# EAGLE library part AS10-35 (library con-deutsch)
DEUTSCH Connector

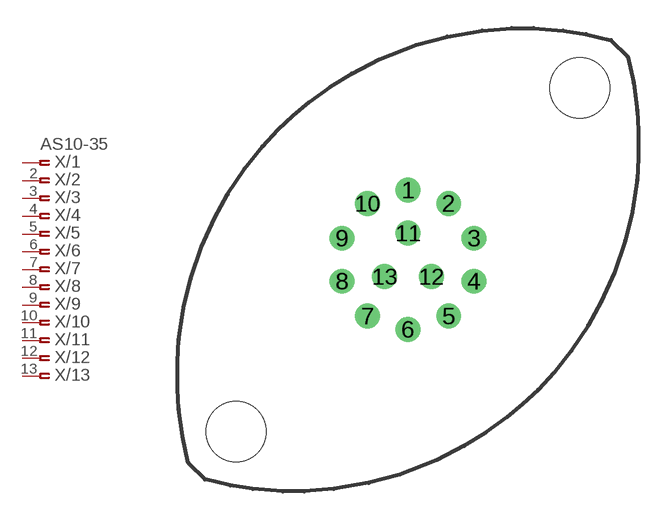
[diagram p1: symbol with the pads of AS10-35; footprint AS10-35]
Designator prefix X; gates /1=PINF_VAL /2=ASPINF /3=ASPINF /4=ASPINF /5=ASPINF /6=ASPINF /7=ASPINF /8=ASPINF /9=ASPINF /10=ASPINF /11=ASPINF /12=ASPINF /13=ASPINF

## AS10-35  [AS10-35]
1  /1:P$1  pas
2  /2:P$1  pas
3  /3:P$1  pas
4  /4:P$1  pas
5  /5:P$1  pas
6  /6:P$1  pas
7  /7:P$1  pas
8  /8:P$1  pas
9  /9:P$1  pas
10  /10:P$1  pas
11  /11:P$1  pas
12  /12:P$1  pas
13  /13:P$1  pas

## Footprint AS10-35 (pad centres in mm)
DEUTSCH Connector
drill 0.813 round: 1 0,3.708; 2 2.159,2.997; 3 3.505,1.143; 4 3.505,-1.143; 5 2.159,-2.997; 6 0,-3.708; 7 -2.159,-2.997; 8 -3.505,-1.143; 9 -3.505,1.143; 10 -2.159,2.997; 11 0,1.422; 12 1.245,-0.889; 13 -1.245,-0.889
hole 3.2 at 9.144,9.144
hole 3.2 at -9.144,-9.144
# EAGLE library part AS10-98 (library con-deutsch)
DEUTSCH Connector

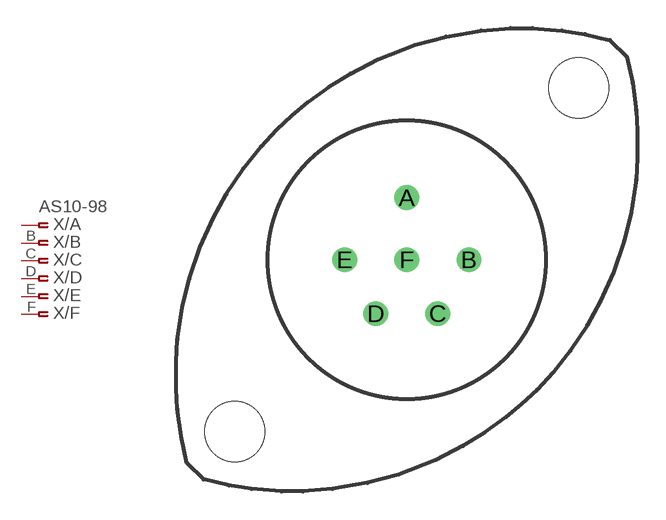
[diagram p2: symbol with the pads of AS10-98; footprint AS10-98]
Designator prefix X; gates /A=PINF_VAL /B=ASPINF /C=ASPINF /D=ASPINF /E=ASPINF /F=ASPINF

## AS10-98  [AS10-98]
A  /A:P$1  pas
B  /B:P$1  pas
C  /C:P$1  pas
D  /D:P$1  pas
E  /E:P$1  pas
F  /F:P$1  pas

## Footprint AS10-98 (pad centres in mm)
DEUTSCH Connector
drill 0.813 round: A 0,3.302; B 3.302,0; C 1.651,-2.87; D -1.651,-2.87; E -3.302,0; F 0,0
hole 3.2 at 9.144,9.144
hole 3.2 at -9.144,-9.144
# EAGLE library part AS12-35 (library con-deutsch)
DEUTSCH Connector

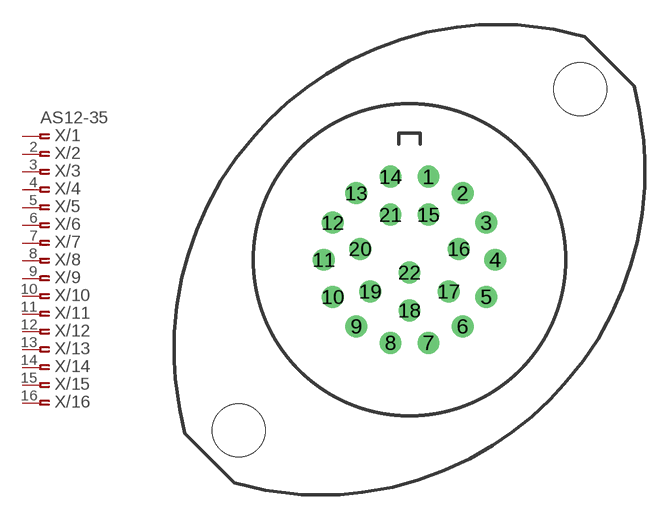
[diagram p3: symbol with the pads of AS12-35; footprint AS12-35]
Designator prefix X; gates /1=PINF_VAL /2=ASPINF /3=ASPINF /4=ASPINF /5=ASPINF /6=ASPINF /7=ASPINF /8=ASPINF /9=ASPINF /10=ASPINF /11=ASPINF /12=ASPINF /13=ASPINF /14=ASPINF /15=ASPINF /16=ASPINF /17=ASPINF /18=ASPINF /19=ASPINF /20=ASPINF /21=ASPINF /22=ASPINF

## AS12-35  [AS12-35]
1  /1:P$1  pas
2  /2:P$1  pas
3  /3:P$1  pas
4  /4:P$1  pas
5  /5:P$1  pas
6  /6:P$1  pas
7  /7:P$1  pas
8  /8:P$1  pas
9  /9:P$1  pas
10  /10:P$1  pas
11  /11:P$1  pas
12  /12:P$1  pas
13  /13:P$1  pas
14  /14:P$1  pas
15  /15:P$1  pas
16  /16:P$1  pas
17  /17:P$1  pas
18  /18:P$1  pas
19  /19:P$1  pas
20  /20:P$1  pas
21  /21:P$1  pas
22  /22:P$1  pas

## Footprint AS12-35 (pad centres in mm)
DEUTSCH Connector
drill 0.813 round: 1 1.143,5.004; 2 3.2,4.013; 3 4.623,2.235; 4 5.156,0; 5 4.623,-2.235; 6 3.2,-4.013; 7 1.143,-5.004; 8 -1.143,-5.004; 9 -3.2,-4.013; 10 -4.623,-2.235; 11 -5.156,0; 12 -4.623,2.235; 13 -3.2,4.013; 14 -1.143,5.004; 15 1.143,2.718; 16 2.972,0.66; 17 2.362,-1.905; 18 0,-3.048; 19 -2.362,-1.905; 20 -2.972,0.66; 21 -1.143,2.718; 22 0,-0.762
hole 3.2 at -10.287,-10.287
hole 3.2 at 10.287,10.287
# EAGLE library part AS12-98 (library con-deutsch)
DEUTSCH Connector

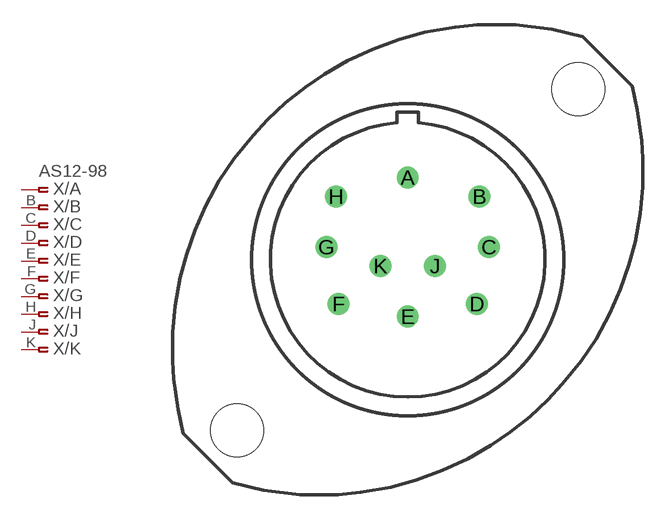
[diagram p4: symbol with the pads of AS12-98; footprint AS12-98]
Designator prefix X; gates /A=PINF_VAL /B=ASPINF /C=ASPINF /D=ASPINF /E=ASPINF /F=ASPINF /G=ASPINF /H=ASPINF /J=ASPINF /K=ASPINF

## AS12-98  [AS12-98]
A  /A:P$1  pas
B  /B:P$1  pas
C  /C:P$1  pas
D  /D:P$1  pas
E  /E:P$1  pas
F  /F:P$1  pas
G  /G:P$1  pas
H  /H:P$1  pas
J  /J:P$1  pas
K  /K:P$1  pas

## Footprint AS12-98 (pad centres in mm)
DEUTSCH Connector
drill 0.813 round: A 0,4.953; B 4.318,3.81; C 4.902,0.762; D 4.166,-2.667; E 0,-3.429; F -4.166,-2.667; G -4.902,0.762; H -4.318,3.81; J 1.651,-0.381; K -1.651,-0.381
hole 3.2 at -10.287,-10.287
hole 3.2 at 10.287,10.287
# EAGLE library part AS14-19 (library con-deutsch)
DEUTSCH Connector

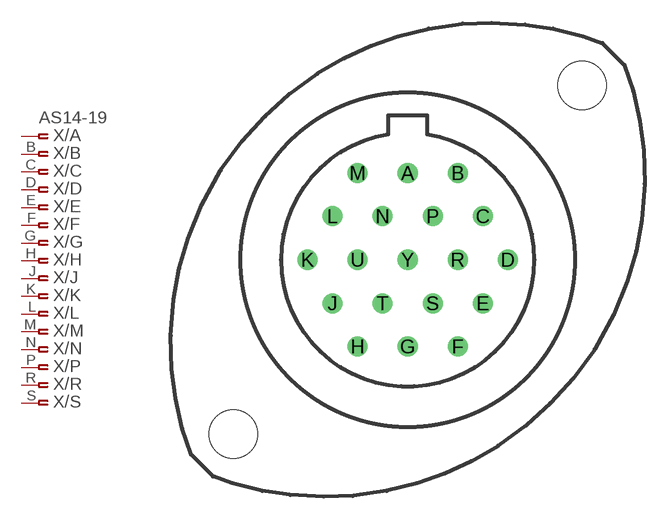
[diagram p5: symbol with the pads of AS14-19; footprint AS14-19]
Designator prefix X; gates /A=PINF_VAL /B=ASPINF /C=ASPINF /D=ASPINF /E=ASPINF /F=ASPINF /G=ASPINF /H=ASPINF /J=ASPINF /K=ASPINF /L=ASPINF /M=ASPINF /N=ASPINF /P=ASPINF /R=ASPINF /S=ASPINF /T=ASPINF /U=ASPINF /Y=ASPINF

## AS14-19  [AS14-19]
A  /A:P$1  pas
B  /B:P$1  pas
C  /C:P$1  pas
D  /D:P$1  pas
E  /E:P$1  pas
F  /F:P$1  pas
G  /G:P$1  pas
H  /H:P$1  pas
J  /J:P$1  pas
K  /K:P$1  pas
L  /L:P$1  pas
M  /M:P$1  pas
N  /N:P$1  pas
P  /P:P$1  pas
R  /R:P$1  pas
S  /S:P$1  pas
T  /T:P$1  pas
U  /U:P$1  pas
Y  /Y:P$1  pas

## Footprint AS14-19 (pad centres in mm)
DEUTSCH Connector
drill 0.813 round: A 0,5.715; B 3.302,5.715; C 4.953,2.87; D 6.604,0; E 4.953,-2.87; F 3.302,-5.715; G 0,-5.715; H -3.302,-5.715; J -4.953,-2.87; K -6.604,0; L -4.953,2.87; M -3.302,5.715; N -1.651,2.87; P 1.651,2.87; R 3.302,0; S 1.651,-2.87; T -1.651,-2.87; U -3.302,0; Y 0,0
hole 3.2 at 11.493,11.493
hole 3.2 at -11.493,-11.493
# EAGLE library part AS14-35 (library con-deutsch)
DEUTSCH Connector

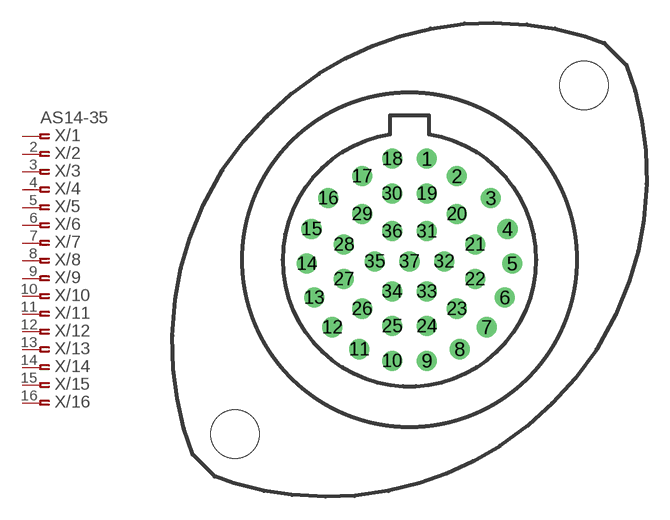
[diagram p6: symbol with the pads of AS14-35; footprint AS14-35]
Designator prefix X; gates /1=PINF_VAL /2=ASPINF /3=ASPINF /4=ASPINF /5=ASPINF /6=ASPINF /7=ASPINF /8=ASPINF /9=ASPINF /10=ASPINF /11=ASPINF /12=ASPINF /13=ASPINF /14=ASPINF /15=ASPINF /16=ASPINF /17=ASPINF /18=ASPINF /19=ASPINF /20=ASPINF /21=ASPINF /22=ASPINF /23=ASPINF /24=ASPINF /25=ASPINF /26=ASPINF /27=ASPINF /28=ASPINF /29=ASPINF /30=ASPINF /31=ASPINF /32=ASPINF /33=ASPINF /34=ASPINF /35=ASPINF /36=ASPINF /37=ASPINF

## AS14-35  [AS14-35]
1  /1:P$1  pas
2  /2:P$1  pas
3  /3:P$1  pas
4  /4:P$1  pas
5  /5:P$1  pas
6  /6:P$1  pas
7  /7:P$1  pas
8  /8:P$1  pas
9  /9:P$1  pas
10  /10:P$1  pas
11  /11:P$1  pas
12  /12:P$1  pas
13  /13:P$1  pas
14  /14:P$1  pas
15  /15:P$1  pas
16  /16:P$1  pas
17  /17:P$1  pas
18  /18:P$1  pas
19  /19:P$1  pas
20  /20:P$1  pas
21  /21:P$1  pas
22  /22:P$1  pas
23  /23:P$1  pas
24  /24:P$1  pas
25  /25:P$1  pas
26  /26:P$1  pas
27  /27:P$1  pas
28  /28:P$1  pas
29  /29:P$1  pas
30  /30:P$1  pas
31  /31:P$1  pas
32  /32:P$1  pas
33  /33:P$1  pas
34  /34:P$1  pas
35  /35:P$1  pas
36  /36:P$1  pas
37  /37:P$1  pas

## Footprint AS14-35 (pad centres in mm)
DEUTSCH Connector
drill 0.813 round: 1 1.143,6.655; 2 3.124,5.512; 3 5.359,4.064; 4 6.452,2.032; 5 6.756,-0.254; 6 6.274,-2.489; 7 5.08,-4.445; 8 3.302,-5.893; 9 1.143,-6.655; 10 -1.143,-6.655; 11 -3.302,-5.893; 12 -5.08,-4.445; 13 -6.274,-2.489; 14 -6.756,-0.254; 15 -6.452,2.032; 16 -5.359,4.064; 17 -3.124,5.512; 18 -1.143,6.655; 19 1.143,4.369; 20 3.124,3.023; 21 4.318,1.016; 22 4.318,-1.27; 23 3.124,-3.226; 24 1.143,-4.369; 25 -1.143,-4.369; 26 -3.124,-3.226; 27 -4.318,-1.27; 28 -4.318,1.016; 29 -3.124,3.023; 30 -1.143,4.369; 31 1.143,1.88; 32 2.286,-0.102; 33 1.143,-2.083; 34 -1.143,-2.083; 35 -2.286,-0.102; 36 -1.143,1.88; 37 0,-0.102
hole 3.2 at 11.493,11.493
hole 3.2 at -11.493,-11.493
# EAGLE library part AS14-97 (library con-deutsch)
DEUTSCH Connector

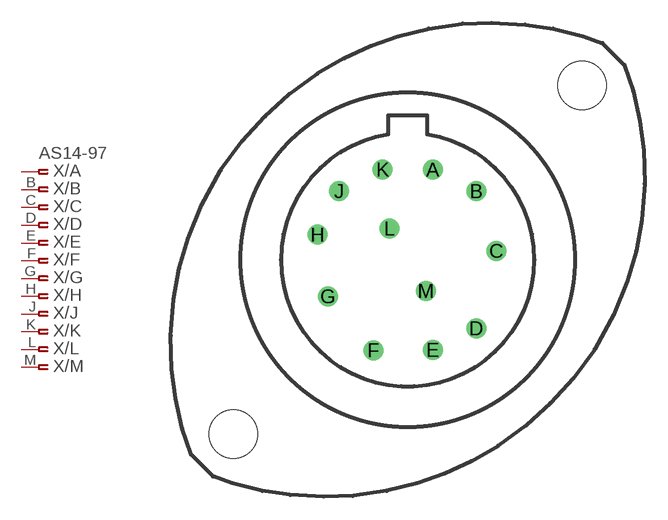
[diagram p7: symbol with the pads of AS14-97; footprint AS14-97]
Designator prefix X; gates /A=PINF_VAL /B=ASPINF /C=ASPINF /D=ASPINF /E=ASPINF /F=ASPINF /G=ASPINF /H=ASPINF /J=ASPINF /K=ASPINF /L=ASPINF /M=ASPINF

## AS14-97  [AS14-97]
A  /A:P$1  pas
B  /B:P$1  pas
C  /C:P$1  pas
D  /D:P$1  pas
E  /E:P$1  pas
F  /F:P$1  pas
G  /G:P$1  pas
H  /H:P$1  pas
J  /J:P$1  pas
K  /K:P$1  pas
L  /L:P$1  pas
M  /M:P$1  pas

## Footprint AS14-97 (pad centres in mm)
DEUTSCH Connector
drill 0.813 round: A 1.651,5.944; B 4.521,4.521; C 5.842,0.584; D 4.521,-4.521; E 1.651,-5.944; F -2.261,-5.969; G -5.258,-2.413; H -5.944,1.651; J -4.521,4.521; K -1.651,5.944; L -1.194,2.057; M 1.194,-2.057
hole 3.2 at 11.493,11.493
hole 3.2 at -11.493,-11.493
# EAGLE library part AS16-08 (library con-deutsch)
DEUTSCH Connector

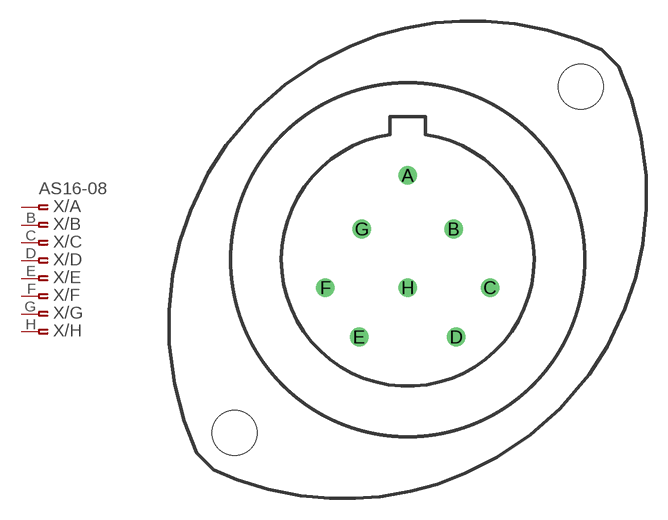
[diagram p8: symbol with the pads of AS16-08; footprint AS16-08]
Designator prefix X; gates /A=PINF_VAL /B=ASPINF /C=ASPINF /D=ASPINF /E=ASPINF /F=ASPINF /G=ASPINF /H=ASPINF

## AS16-08  [AS16-08]
A  /A:P$1  pas
B  /B:P$1  pas
C  /C:P$1  pas
D  /D:P$1  pas
E  /E:P$1  pas
F  /F:P$1  pas
G  /G:P$1  pas
H  /H:P$1  pas

## Footprint AS16-08 (pad centres in mm)
DEUTSCH Connector
drill 0.813 round: A 0,5.994; B 3.251,2.184; C 5.842,-1.981; D 3.454,-5.486; E -3.454,-5.486; F -5.842,-1.981; G -3.251,2.184; H 0,-1.981
hole 3.2 at 12.29,12.29
hole 3.2 at -12.29,-12.29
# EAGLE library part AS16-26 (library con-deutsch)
DEUTSCH Connector

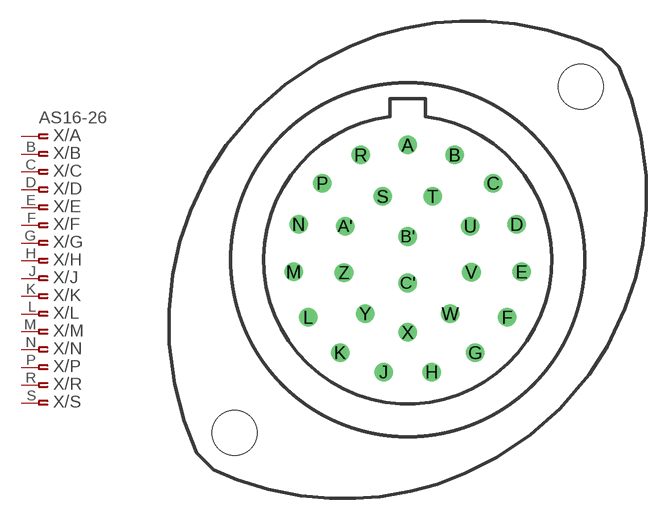
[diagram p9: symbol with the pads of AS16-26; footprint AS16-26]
Designator prefix X; gates /A=PINF_VAL /B=ASPINF /C=ASPINF /D=ASPINF /E=ASPINF /F=ASPINF /G=ASPINF /H=ASPINF /J=ASPINF /K=ASPINF /L=ASPINF /M=ASPINF /N=ASPINF /P=ASPINF /R=ASPINF /S=ASPINF /T=ASPINF /U=ASPINF /V=ASPINF /W=ASPINF /X=ASPINF /Y=ASPINF /Z=ASPINF /B'=ASPINF /C'=ASPINF /A'=ASPINF

## AS16-26  [AS16-26]
A  /A:P$1  pas
A'  /A':P$1  pas
B  /B:P$1  pas
B'  /B':P$1  pas
C  /C:P$1  pas
C'  /C':P$1  pas
D  /D:P$1  pas
E  /E:P$1  pas
F  /F:P$1  pas
G  /G:P$1  pas
H  /H:P$1  pas
J  /J:P$1  pas
K  /K:P$1  pas
L  /L:P$1  pas
M  /M:P$1  pas
N  /N:P$1  pas
P  /P:P$1  pas
R  /R:P$1  pas
S  /S:P$1  pas
T  /T:P$1  pas
U  /U:P$1  pas
V  /V:P$1  pas
W  /W:P$1  pas
X  /X:P$1  pas
Y  /Y:P$1  pas
Z  /Z:P$1  pas

## Footprint AS16-26 (pad centres in mm)
DEUTSCH Connector
drill 0.813 round: A 0,8.153; A' -4.445,2.388; B 3.327,7.442; B' 0,1.651; C 6.071,5.436; C' 0,-1.651; D 7.747,2.515; E 8.103,-0.864; F 7.061,-4.089; G 4.801,-6.604; H 1.702,-7.976; J -1.702,-7.976; K -4.801,-6.604; L -7.061,-4.089; M -8.103,-0.864; N -7.747,2.515; P -6.071,5.436; R -3.327,7.442; S -1.778,4.496; T 1.778,4.496; U 4.445,2.388; V 4.521,-0.889; W 3.023,-3.835; X 0,-5.156; Y -3.023,-3.835; Z -4.521,-0.914
hole 3.2 at 12.29,12.29
hole 3.2 at -12.29,-12.29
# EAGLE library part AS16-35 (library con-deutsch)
DEUTSCH Connector

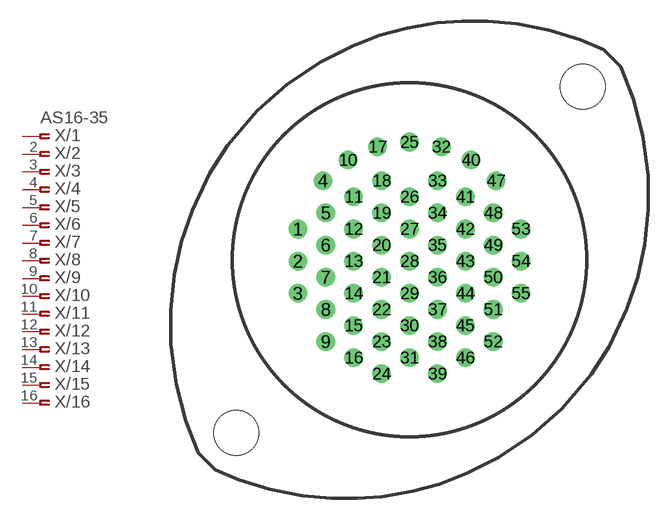
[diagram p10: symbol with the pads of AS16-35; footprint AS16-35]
Designator prefix X; gates /1=PINF_VAL /2=ASPINF /3=ASPINF /4=ASPINF /5=ASPINF /6=ASPINF /7=ASPINF /8=ASPINF /9=ASPINF /10=ASPINF /11=ASPINF /12=ASPINF /13=ASPINF /14=ASPINF /15=ASPINF /16=ASPINF /17=ASPINF /18=ASPINF /19=ASPINF /20=ASPINF /21=ASPINF /22=ASPINF /23=ASPINF /24=ASPINF /25=ASPINF /26=ASPINF /27=ASPINF /28=ASPINF /29=ASPINF /30=ASPINF /31=ASPINF /32=ASPINF /33=ASPINF /34=ASPINF /35=ASPINF /36=ASPINF /37=ASPINF /38=ASPINF /39=ASPINF /40=ASPINF /41=ASPINF /42=ASPINF /43=ASPINF /44=ASPINF /45=ASPINF /46=ASPINF /47=ASPINF /48=ASPINF /49=ASPINF /50=ASPINF /51=ASPINF /52=ASPINF /53=ASPINF /54=ASPINF /55=ASPINF

## AS16-35  [AS16-35]
1  /1:P$1  pas
2  /2:P$1  pas
3  /3:P$1  pas
4  /4:P$1  pas
5  /5:P$1  pas
6  /6:P$1  pas
7  /7:P$1  pas
8  /8:P$1  pas
9  /9:P$1  pas
10  /10:P$1  pas
11  /11:P$1  pas
12  /12:P$1  pas
13  /13:P$1  pas
14  /14:P$1  pas
15  /15:P$1  pas
16  /16:P$1  pas
17  /17:P$1  pas
18  /18:P$1  pas
19  /19:P$1  pas
20  /20:P$1  pas
21  /21:P$1  pas
22  /22:P$1  pas
23  /23:P$1  pas
24  /24:P$1  pas
25  /25:P$1  pas
26  /26:P$1  pas
27  /27:P$1  pas
28  /28:P$1  pas
29  /29:P$1  pas
30  /30:P$1  pas
31  /31:P$1  pas
32  /32:P$1  pas
33  /33:P$1  pas
34  /34:P$1  pas
35  /35:P$1  pas
36  /36:P$1  pas
37  /37:P$1  pas
38  /38:P$1  pas
39  /39:P$1  pas
40  /40:P$1  pas
41  /41:P$1  pas
42  /42:P$1  pas
43  /43:P$1  pas
44  /44:P$1  pas
45  /45:P$1  pas
46  /46:P$1  pas
47  /47:P$1  pas
48  /48:P$1  pas
49  /49:P$1  pas
50  /50:P$1  pas
51  /51:P$1  pas
52  /52:P$1  pas
53  /53:P$1  pas
54  /54:P$1  pas
55  /55:P$1  pas

## Footprint AS16-35 (pad centres in mm)
DEUTSCH Connector
drill 0.813 round: 1 -7.925,2.184; 2 -7.925,-0.102; 3 -7.925,-2.388; 4 -6.147,5.613; 5 -5.944,3.327; 6 -5.944,1.041; 7 -5.944,-1.245; 8 -5.944,-3.531; 9 -5.944,-5.817; 10 -4.369,7.087; 11 -3.962,4.47; 12 -3.962,2.184; 13 -3.962,-0.102; 14 -3.962,-2.388; 15 -3.962,-4.674; 16 -3.962,-6.96; 17 -2.261,8.026; 18 -1.981,5.613; 19 -1.981,3.327; 20 -1.981,1.041; 21 -1.981,-1.245; 22 -1.981,-3.531; 23 -1.981,-5.817; 24 -1.981,-8.103; 25 0,8.357; 26 0,4.47; 27 0,2.184; 28 0,-0.102; 29 0,-2.388; 30 0,-4.674; 31 0,-6.96; 32 2.261,8.026; 33 1.981,5.613; 34 1.981,3.327; 35 1.981,1.041; 36 1.981,-1.245; 37 1.981,-3.531; 38 1.981,-5.817; 39 1.981,-8.103; 40 4.369,7.087; 41 3.962,4.47; 42 3.962,2.184; 43 3.962,-0.102; 44 3.962,-2.388; 45 3.962,-4.674; 46 3.962,-6.96; 47 6.147,5.613; 48 5.944,3.327; 49 5.944,1.041; 50 5.944,-1.245; 51 5.944,-3.531; 52 5.944,-5.817; 53 7.925,2.184; 54 7.925,-0.102; 55 7.925,-2.388
hole 3.2 at 12.29,12.29
hole 3.2 at -12.29,-12.29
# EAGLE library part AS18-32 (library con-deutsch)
DEUTSCH Connector

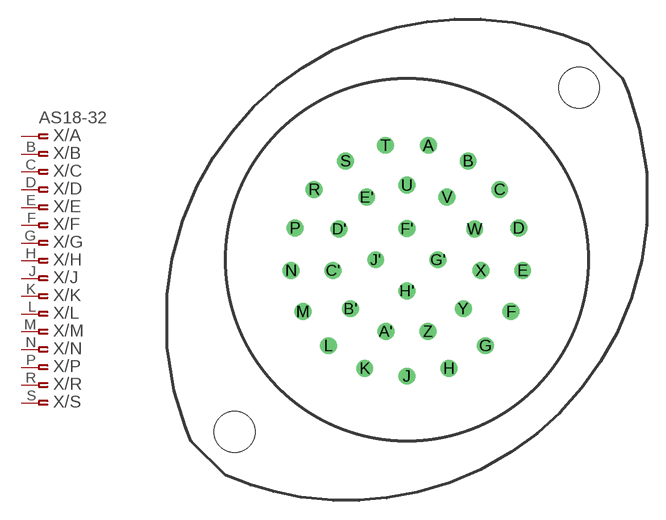
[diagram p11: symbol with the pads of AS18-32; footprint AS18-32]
Designator prefix X; gates /A=PINF_VAL /B=ASPINF /C=ASPINF /D=ASPINF /E=ASPINF /F=ASPINF /G=ASPINF /H=ASPINF /J=ASPINF /K=ASPINF /L=ASPINF /M=ASPINF /N=ASPINF /P=ASPINF /R=ASPINF /S=ASPINF /T=ASPINF /U=ASPINF /V=ASPINF /W=ASPINF /X=ASPINF /Y=ASPINF /Z=ASPINF /A'=PINF_VAL /B'=ASPINF /C'=ASPINF /D'=ASPINF /E'=ASPINF /F'=ASPINF /G'=ASPINF /H'=ASPINF /J'=ASPINF

## AS18-32  [AS18-32]
A  /A:P$1  pas
A'  /A':P$1  pas
B  /B:P$1  pas
B'  /B':P$1  pas
C  /C:P$1  pas
C'  /C':P$1  pas
D  /D:P$1  pas
D'  /D':P$1  pas
E  /E:P$1  pas
E'  /E':P$1  pas
F  /F:P$1  pas
F'  /F':P$1  pas
G  /G:P$1  pas
G'  /G':P$1  pas
H  /H:P$1  pas
H'  /H':P$1  pas
J  /J:P$1  pas
J'  /J':P$1  pas
K  /K:P$1  pas
L  /L:P$1  pas
M  /M:P$1  pas
N  /N:P$1  pas
P  /P:P$1  pas
R  /R:P$1  pas
S  /S:P$1  pas
T  /T:P$1  pas
U  /U:P$1  pas
V  /V:P$1  pas
W  /W:P$1  pas
X  /X:P$1  pas
Y  /Y:P$1  pas
Z  /Z:P$1  pas

## Footprint AS18-32 (pad centres in mm)
DEUTSCH Connector
drill 0.813 round: A 1.676,8.966; A' -1.651,-5.613; B 4.801,7.747; B' -4.42,-3.835; C 7.264,5.512; C' -5.791,-0.838; D 8.763,2.489; D' -5.309,2.413; E 9.068,-0.838; E' -3.15,4.902; F 8.153,-4.064; F' 0,2.438; G 6.147,-6.731; G' 2.438,0; H 3.302,-8.509; H' 0,-2.438; J 0,-9.119; J' -2.438,0; K -3.302,-8.509; L -6.147,-6.731; M -8.153,-4.064; N -9.068,-0.838; P -8.763,2.489; R -7.264,5.512; S -4.801,7.747; T -1.676,8.966; U 0,5.842; V 3.15,4.902; W 5.309,2.413; X 5.791,-0.838; Y 4.42,-3.835; Z 1.651,-5.613
hole 3.2 at -13.49,-13.49
hole 3.2 at 13.49,13.49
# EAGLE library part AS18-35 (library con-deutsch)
DEUTSCH Connector

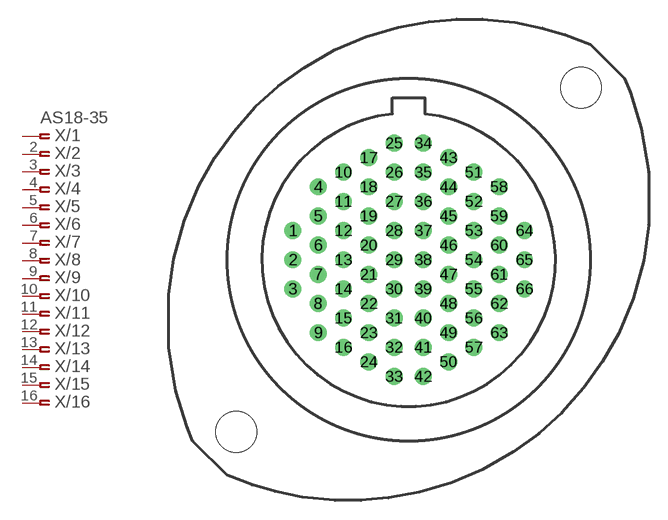
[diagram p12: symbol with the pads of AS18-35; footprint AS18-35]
Designator prefix X; gates /1=PINF_VAL /2=ASPINF /3=ASPINF /4=ASPINF /5=ASPINF /6=ASPINF /7=ASPINF /8=ASPINF /9=ASPINF /10=ASPINF /11=ASPINF /12=ASPINF /13=ASPINF /14=ASPINF /15=ASPINF /16=ASPINF /17=ASPINF /18=ASPINF /19=ASPINF /20=ASPINF /21=ASPINF /22=ASPINF /23=ASPINF /24=ASPINF /25=ASPINF /26=ASPINF /27=ASPINF /28=ASPINF /29=ASPINF /30=ASPINF /31=ASPINF /32=ASPINF /33=ASPINF /34=ASPINF /35=ASPINF /36=ASPINF /37=ASPINF /38=ASPINF /39=ASPINF /40=ASPINF /41=ASPINF /42=ASPINF /43=ASPINF /44=ASPINF /45=ASPINF /46=ASPINF /47=ASPINF /48=ASPINF /49=ASPINF /50=ASPINF /51=ASPINF /52=ASPINF /53=ASPINF /54=ASPINF /55=ASPINF /56=ASPINF /57=ASPINF /58=ASPINF /59=ASPINF /60=ASPINF /61=ASPINF /62=ASPINF /63=ASPINF /64=ASPINF /65=ASPINF /66=ASPINF

## AS18-35  [AS18-35]
1  /1:P$1  pas
2  /2:P$1  pas
3  /3:P$1  pas
4  /4:P$1  pas
5  /5:P$1  pas
6  /6:P$1  pas
7  /7:P$1  pas
8  /8:P$1  pas
9  /9:P$1  pas
10  /10:P$1  pas
11  /11:P$1  pas
12  /12:P$1  pas
13  /13:P$1  pas
14  /14:P$1  pas
15  /15:P$1  pas
16  /16:P$1  pas
17  /17:P$1  pas
18  /18:P$1  pas
19  /19:P$1  pas
20  /20:P$1  pas
21  /21:P$1  pas
22  /22:P$1  pas
23  /23:P$1  pas
24  /24:P$1  pas
25  /25:P$1  pas
26  /26:P$1  pas
27  /27:P$1  pas
28  /28:P$1  pas
29  /29:P$1  pas
30  /30:P$1  pas
31  /31:P$1  pas
32  /32:P$1  pas
33  /33:P$1  pas
34  /34:P$1  pas
35  /35:P$1  pas
36  /36:P$1  pas
37  /37:P$1  pas
38  /38:P$1  pas
39  /39:P$1  pas
40  /40:P$1  pas
41  /41:P$1  pas
42  /42:P$1  pas
43  /43:P$1  pas
44  /44:P$1  pas
45  /45:P$1  pas
46  /46:P$1  pas
47  /47:P$1  pas
48  /48:P$1  pas
49  /49:P$1  pas
50  /50:P$1  pas
51  /51:P$1  pas
52  /52:P$1  pas
53  /53:P$1  pas
54  /54:P$1  pas
55  /55:P$1  pas
56  /56:P$1  pas
57  /57:P$1  pas
58  /58:P$1  pas
59  /59:P$1  pas
60  /60:P$1  pas
61  /61:P$1  pas
62  /62:P$1  pas
63  /63:P$1  pas
64  /64:P$1  pas
65  /65:P$1  pas
66  /66:P$1  pas

## Footprint AS18-35 (pad centres in mm)
DEUTSCH Connector
drill 0.813 round: 1 -9.068,2.286; 2 -9.068,0; 3 -9.068,-2.286; 4 -7.087,5.715; 5 -7.087,3.429; 6 -7.087,1.143; 7 -7.087,-1.143; 8 -7.087,-3.429; 9 -7.087,-5.715; 10 -5.105,6.858; 11 -5.105,4.572; 12 -5.105,2.286; 13 -5.105,0; 14 -5.105,-2.286; 15 -5.105,-4.572; 16 -5.105,-6.858; 17 -3.124,8.001; 18 -3.124,5.715; 19 -3.124,3.429; 20 -3.124,1.143; 21 -3.124,-1.143; 22 -3.124,-3.429; 23 -3.124,-5.715; 24 -3.124,-8.001; 25 -1.143,9.144; 26 -1.143,6.858; 27 -1.143,4.572; 28 -1.143,2.286; 29 -1.143,0; 30 -1.143,-2.286; 31 -1.143,-4.572; 32 -1.143,-6.858; 33 -1.143,-9.144; 34 1.143,9.144; 35 1.143,6.858; 36 1.143,4.572; 37 1.143,2.286; 38 1.143,0; 39 1.143,-2.286; 40 1.143,-4.572; 41 1.143,-6.858; 42 1.143,-9.144; 43 3.124,8.001; 44 3.124,5.715; 45 3.124,3.429; 46 3.124,1.143; 47 3.124,-1.143; 48 3.124,-3.429; 49 3.124,-5.715; 50 3.124,-8.001; 51 5.105,6.858; 52 5.105,4.572; 53 5.105,2.286; 54 5.105,0; 55 5.105,-2.286; 56 5.105,-4.572; 57 5.105,-6.858; 58 7.087,5.715; 59 7.087,3.429; 60 7.087,1.143; 61 7.087,-1.143; 62 7.087,-3.429; 63 7.087,-5.715; 64 9.068,2.286; 65 9.068,0; 66 9.068,-2.286
hole 3.2 at -13.49,-13.49
hole 3.2 at 13.49,13.49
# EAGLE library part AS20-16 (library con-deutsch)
DEUTSCH Connector

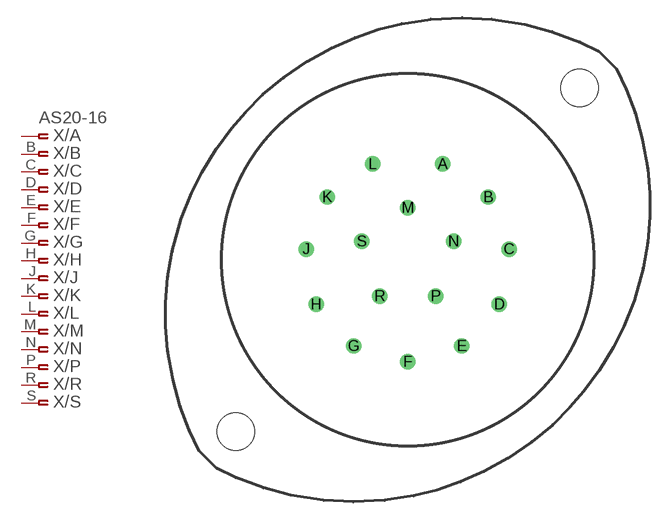
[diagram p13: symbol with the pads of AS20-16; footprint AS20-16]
Designator prefix X; gates /A=PINF_VAL /B=ASPINF /C=ASPINF /D=ASPINF /E=ASPINF /F=ASPINF /G=ASPINF /H=ASPINF /J=ASPINF /K=ASPINF /L=ASPINF /M=ASPINF /N=ASPINF /P=ASPINF /R=ASPINF /S=ASPINF

## AS20-16  [AS20-16]
A  /A:P$1  pas
B  /B:P$1  pas
C  /C:P$1  pas
D  /D:P$1  pas
E  /E:P$1  pas
F  /F:P$1  pas
G  /G:P$1  pas
H  /H:P$1  pas
J  /J:P$1  pas
K  /K:P$1  pas
L  /L:P$1  pas
M  /M:P$1  pas
N  /N:P$1  pas
P  /P:P$1  pas
R  /R:P$1  pas
S  /S:P$1  pas

## Footprint AS20-16 (pad centres in mm)
DEUTSCH Connector
drill 0.813 round: A 2.997,8.179; B 6.883,5.359; C 8.661,0.914; D 7.823,-3.81; E 4.623,-7.366; F 0,-8.712; G -4.623,-7.366; H -7.823,-3.81; J -8.661,0.914; K -6.883,5.359; L -2.997,8.179; M 0,4.445; N 3.912,1.575; P 2.388,-3.099; R -2.388,-3.099; S -3.912,1.575
hole 3.2 at -14.7,-14.7
hole 3.2 at 14.7,14.7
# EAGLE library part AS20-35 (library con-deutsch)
DEUTSCH Connector

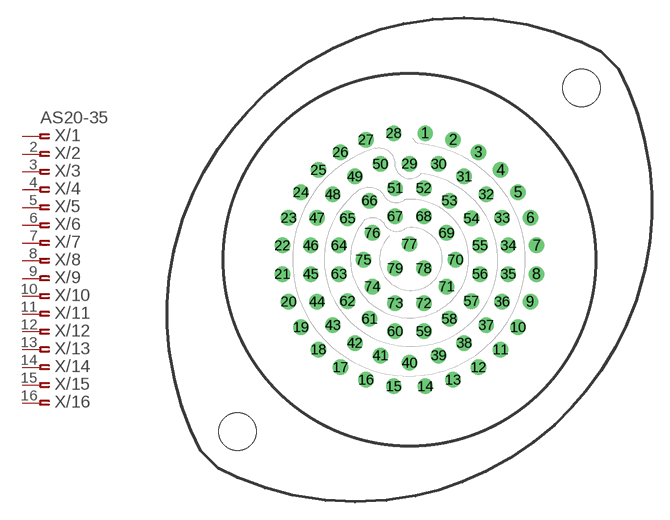
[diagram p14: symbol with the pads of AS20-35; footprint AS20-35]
Designator prefix X; gates /1=PINF_VAL /2=ASPINF /3=ASPINF /4=ASPINF /5=ASPINF /6=ASPINF /7=ASPINF /8=ASPINF /9=ASPINF /10=ASPINF /11=ASPINF /12=ASPINF /13=ASPINF /14=ASPINF /15=ASPINF /16=ASPINF /17=ASPINF /18=ASPINF /19=ASPINF /20=ASPINF /21=ASPINF /22=ASPINF /23=ASPINF /24=ASPINF /25=ASPINF /26=ASPINF /27=ASPINF /28=ASPINF /29=ASPINF /30=ASPINF /31=ASPINF /32=ASPINF /33=ASPINF /34=ASPINF /35=ASPINF /36=ASPINF /37=ASPINF /38=ASPINF /39=ASPINF /40=ASPINF /41=ASPINF /42=ASPINF /43=ASPINF /44=ASPINF /45=ASPINF /46=ASPINF /47=ASPINF /48=ASPINF /49=ASPINF /50=ASPINF /51=ASPINF /52=ASPINF /53=ASPINF /54=ASPINF /55=ASPINF /56=ASPINF /57=ASPINF /58=ASPINF /59=ASPINF /60=ASPINF /61=ASPINF /62=ASPINF /63=ASPINF /64=ASPINF /65=ASPINF /66=ASPINF /67=ASPINF /68=ASPINF /69=ASPINF /70=ASPINF /71=ASPINF /72=ASPINF /73=ASPINF /74=ASPINF /75=ASPINF /76=ASPINF /77=ASPINF /78=ASPINF /79=ASPINF

## AS20-35  [AS20-35]
1  /1:P$1  pas
2  /2:P$1  pas
3  /3:P$1  pas
4  /4:P$1  pas
5  /5:P$1  pas
6  /6:P$1  pas
7  /7:P$1  pas
8  /8:P$1  pas
9  /9:P$1  pas
10  /10:P$1  pas
11  /11:P$1  pas
12  /12:P$1  pas
13  /13:P$1  pas
14  /14:P$1  pas
15  /15:P$1  pas
16  /16:P$1  pas
17  /17:P$1  pas
18  /18:P$1  pas
19  /19:P$1  pas
20  /20:P$1  pas
21  /21:P$1  pas
22  /22:P$1  pas
23  /23:P$1  pas
24  /24:P$1  pas
25  /25:P$1  pas
26  /26:P$1  pas
27  /27:P$1  pas
28  /28:P$1  pas
29  /29:P$1  pas
30  /30:P$1  pas
31  /31:P$1  pas
32  /32:P$1  pas
33  /33:P$1  pas
34  /34:P$1  pas
35  /35:P$1  pas
36  /36:P$1  pas
37  /37:P$1  pas
38  /38:P$1  pas
39  /39:P$1  pas
40  /40:P$1  pas
41  /41:P$1  pas
42  /42:P$1  pas
43  /43:P$1  pas
44  /44:P$1  pas
45  /45:P$1  pas
46  /46:P$1  pas
47  /47:P$1  pas
48  /48:P$1  pas
49  /49:P$1  pas
50  /50:P$1  pas
51  /51:P$1  pas
52  /52:P$1  pas
53  /53:P$1  pas
54  /54:P$1  pas
55  /55:P$1  pas
56  /56:P$1  pas
57  /57:P$1  pas
58  /58:P$1  pas
59  /59:P$1  pas
60  /60:P$1  pas
61  /61:P$1  pas
62  /62:P$1  pas
63  /63:P$1  pas
64  /64:P$1  pas
65  /65:P$1  pas
66  /66:P$1  pas
67  /67:P$1  pas
68  /68:P$1  pas
69  /69:P$1  pas
70  /70:P$1  pas
71  /71:P$1  pas
72  /72:P$1  pas
73  /73:P$1  pas
74  /74:P$1  pas
75  /75:P$1  pas
76  /76:P$1  pas
77  /77:P$1  pas
78  /78:P$1  pas
79  /79:P$1  pas

## Footprint AS20-35 (pad centres in mm)
DEUTSCH Connector
drill 0.813 round: 1 1.346,10.82; 2 3.708,10.262; 3 5.893,9.195; 4 7.772,7.671; 5 9.271,5.766; 6 10.312,3.581; 7 10.846,1.219; 8 10.846,-1.219; 9 10.312,-3.581; 10 9.271,-5.766; 11 7.772,-7.671; 12 5.893,-9.195; 13 3.708,-10.262; 14 1.346,-10.82; 15 -1.346,-10.82; 16 -3.708,-10.262; 17 -5.893,-9.195; 18 -7.772,-7.671; 19 -9.271,-5.766; 20 -10.312,-3.581; 21 -10.846,-1.219; 22 -10.846,1.219; 23 -10.312,3.581; 24 -9.271,5.766; 25 -7.772,7.671; 26 -5.893,9.195; 27 -3.708,10.262; 28 -1.346,10.82; 29 0,8.204; 30 2.489,8.179; 31 4.674,7.112; 32 6.553,5.588; 33 7.899,3.581; 34 8.433,1.219; 35 8.433,-1.219; 36 7.899,-3.581; 37 6.553,-5.588; 38 4.674,-7.112; 39 2.489,-8.179; 40 0,-8.814; 41 -2.489,-8.179; 42 -4.674,-7.112; 43 -6.553,-5.588; 44 -7.899,-3.581; 45 -8.433,-1.219; 46 -8.433,1.219; 47 -7.899,3.581; 48 -6.553,5.588; 49 -4.674,7.112; 50 -2.489,8.179; 51 -1.219,6.121; 52 1.219,6.121; 53 3.404,5.055; 54 5.283,3.531; 55 6.02,1.219; 56 6.02,-1.219; 57 5.283,-3.531; 58 3.404,-5.055; 59 1.219,-6.121; 60 -1.219,-6.121; 61 -3.404,-5.055; 62 -5.283,-3.531; 63 -6.02,-1.219; 64 -6.02,1.219; 65 -5.283,3.531; 66 -3.404,5.055; 67 -1.219,3.708; 68 1.219,3.708; 69 3.175,2.286; 70 3.937,0; 71 3.175,-2.286; 72 1.219,-3.708; 73 -1.219,-3.708; 74 -3.175,-2.286; 75 -3.937,0; 76 -3.175,2.286; 77 0,1.346; 78 1.219,-0.737; 79 -1.219,-0.737
hole 3.2 at -14.7,-14.7
hole 3.2 at 14.7,14.7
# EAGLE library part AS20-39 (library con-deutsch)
DEUTSCH Connector

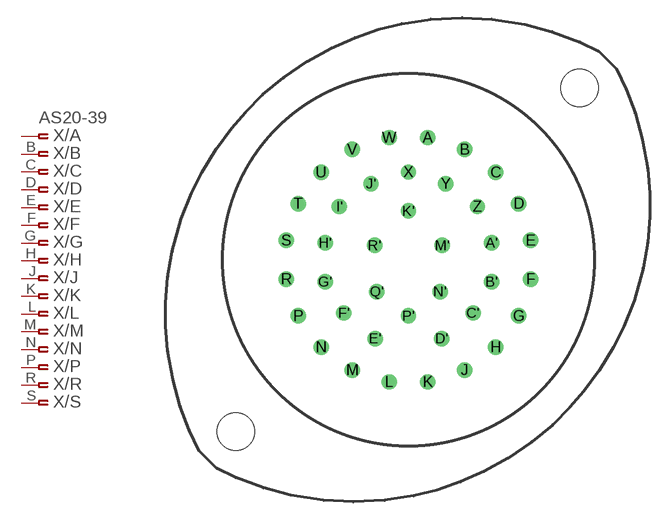
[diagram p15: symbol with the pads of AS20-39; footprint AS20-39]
Designator prefix X; gates /A=PINF_VAL /B=ASPINF /C=ASPINF /D=ASPINF /E=ASPINF /F=ASPINF /G=ASPINF /H=ASPINF /J=ASPINF /K=ASPINF /L=ASPINF /M=ASPINF /N=ASPINF /P=ASPINF /R=ASPINF /S=ASPINF /T=ASPINF /U=ASPINF /V=ASPINF /W=ASPINF /X=ASPINF /Y=ASPINF /Z=ASPINF /A'=PINF_VAL /B'=ASPINF /C'=ASPINF /D'=ASPINF /E'=ASPINF /F'=ASPINF /G'=ASPINF /H'=ASPINF /J'=ASPINF /K'=ASPINF /I'=ASPINF /M'=ASPINF /N'=ASPINF /P'=ASPINF /Q'=ASPINF /R'=ASPINF

## AS20-39  [AS20-39]
A  /A:P$1  pas
A'  /A':P$1  pas
B  /B:P$1  pas
B'  /B':P$1  pas
C  /C:P$1  pas
C'  /C':P$1  pas
D  /D:P$1  pas
D'  /D':P$1  pas
E  /E:P$1  pas
E'  /E':P$1  pas
F  /F:P$1  pas
F'  /F':P$1  pas
G  /G:P$1  pas
G'  /G':P$1  pas
H  /H:P$1  pas
H'  /H':P$1  pas
I'  /I':P$1  pas
J  /J:P$1  pas
J'  /J':P$1  pas
K  /K:P$1  pas
K'  /K':P$1  pas
L  /L:P$1  pas
M  /M:P$1  pas
M'  /M':P$1  pas
N  /N:P$1  pas
N'  /N':P$1  pas
P  /P:P$1  pas
P'  /P':P$1  pas
Q'  /Q':P$1  pas
R  /R:P$1  pas
R'  /R':P$1  pas
S  /S:P$1  pas
T  /T:P$1  pas
U  /U:P$1  pas
V  /V:P$1  pas
W  /W:P$1  pas
X  /X:P$1  pas
Y  /Y:P$1  pas
Z  /Z:P$1  pas

## Footprint AS20-39 (pad centres in mm)
DEUTSCH Connector
drill 0.813 round: A 1.651,10.439; A' 7.112,1.448; B 4.801,9.423; B' 7.112,-1.88; C 7.468,7.468; C' 5.512,-4.547; D 9.423,4.801; D' 2.845,-6.731; E 10.439,1.651; E' -2.845,-6.731; F 10.439,-1.651; F' -5.512,-4.547; G 9.423,-4.801; G' -7.112,-1.88; H 7.468,-7.468; H' -7.112,1.448; I' -5.893,4.547; J 4.801,-9.423; J' -3.2,6.502; K 1.651,-10.439; K' 0,4.166; L -1.651,-10.439; M -4.801,-9.423; M' 2.896,1.219; N -7.468,-7.468; N' 2.692,-2.718; P -9.423,-4.801; P' 0,-4.801; Q' -2.692,-2.718; R -10.439,-1.651; R' -2.896,1.219; S -10.439,1.651; T -9.423,4.801; U -7.468,7.468; V -4.801,9.423; W -1.651,10.439; X 0,7.493; Y 3.2,6.502; Z 5.893,4.547
hole 3.2 at -14.764,-14.7
hole 3.2 at 14.636,14.7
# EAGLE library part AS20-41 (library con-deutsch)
DEUTSCH Connector

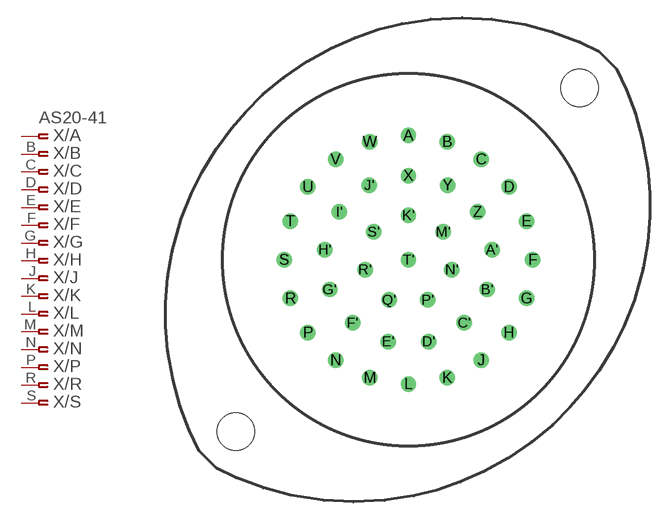
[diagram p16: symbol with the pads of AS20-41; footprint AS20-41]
Designator prefix X; gates /A=PINF_VAL /B=ASPINF /C=ASPINF /D=ASPINF /E=ASPINF /F=ASPINF /G=ASPINF /H=ASPINF /J=ASPINF /K=ASPINF /L=ASPINF /M=ASPINF /N=ASPINF /P=ASPINF /R=ASPINF /S=ASPINF /T=ASPINF /U=ASPINF /V=ASPINF /W=ASPINF /X=ASPINF /Y=ASPINF /Z=ASPINF /A'=PINF_VAL /B'=ASPINF /C'=ASPINF /D'=ASPINF /E'=ASPINF /F'=ASPINF /G'=ASPINF /H'=ASPINF /J'=ASPINF /K'=ASPINF /Q'=ASPINF /M'=ASPINF /N'=ASPINF /P'=ASPINF /R'=ASPINF /S'=ASPINF /T'=ASPINF /I'=ASPINF

## AS20-41  [AS20-41]
A  /A:P$1  pas
A'  /A':P$1  pas
B  /B:P$1  pas
B'  /B':P$1  pas
C  /C:P$1  pas
C'  /C':P$1  pas
D  /D:P$1  pas
D'  /D':P$1  pas
E  /E:P$1  pas
E'  /E':P$1  pas
F  /F:P$1  pas
F'  /F':P$1  pas
G  /G:P$1  pas
G'  /G':P$1  pas
H  /H:P$1  pas
H'  /H':P$1  pas
I'  /I':P$1  pas
J  /J:P$1  pas
J'  /J':P$1  pas
K  /K:P$1  pas
K'  /K':P$1  pas
L  /L:P$1  pas
M  /M:P$1  pas
M'  /M':P$1  pas
N  /N:P$1  pas
N'  /N':P$1  pas
P  /P:P$1  pas
P'  /P':P$1  pas
Q'  /Q':P$1  pas
R  /R:P$1  pas
R'  /R':P$1  pas
S  /S:P$1  pas
S'  /S':P$1  pas
T  /T:P$1  pas
T'  /T':P$1  pas
U  /U:P$1  pas
V  /V:P$1  pas
W  /W:P$1  pas
X  /X:P$1  pas
Y  /Y:P$1  pas
Z  /Z:P$1  pas

## Footprint AS20-41 (pad centres in mm)
DEUTSCH Connector
drill 0.813 round: A 0,10.617; A' 7.137,0.864; B 3.302,10.084; B' 6.731,-2.54; C 6.223,8.585; C' 4.775,-5.385; D 8.585,6.223; D' 1.727,-6.985; E 10.084,3.302; E' -1.727,-6.985; F 10.617,0; F' -4.775,-5.385; G 10.084,-3.302; G' -6.731,-2.54; H 8.585,-6.223; H' -7.137,0.864; I' -5.918,4.089; J 6.223,-8.585; J' -3.353,6.375; K 3.302,-10.084; K' 0,3.81; L 0,-10.617; M -3.302,-10.084; M' 2.972,2.388; N -6.223,-8.585; N' 3.708,-0.838; P -8.585,-6.223; P' 1.651,-3.429; Q' -1.651,-3.429; R -10.084,-3.302; R' -3.708,-0.838; S -10.617,0; S' -2.972,2.388; T -10.084,3.302; T' 0,0; U -8.585,6.223; V -6.223,8.585; W -3.302,10.084; X 0,7.188; Y 3.353,6.375; Z 5.918,4.089
hole 3.2 at -14.764,-14.7
hole 3.2 at 14.636,14.7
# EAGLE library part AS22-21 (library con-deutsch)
DEUTSCH Connector

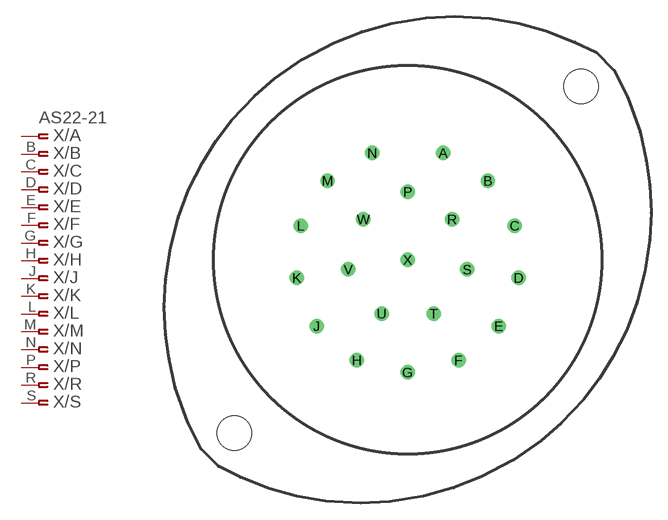
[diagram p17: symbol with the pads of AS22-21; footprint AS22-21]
Designator prefix X; gates /A=PINF_VAL /B=ASPINF /C=ASPINF /D=ASPINF /E=ASPINF /F=ASPINF /G=ASPINF /H=ASPINF /J=ASPINF /K=ASPINF /L=ASPINF /M=ASPINF /N=ASPINF /P=ASPINF /R=ASPINF /S=ASPINF /T=ASPINF /U=ASPINF /V=ASPINF /W=ASPINF /X=ASPINF

## AS22-21  [AS22-21]
A  /A:P$1  pas
B  /B:P$1  pas
C  /C:P$1  pas
D  /D:P$1  pas
E  /E:P$1  pas
F  /F:P$1  pas
G  /G:P$1  pas
H  /H:P$1  pas
J  /J:P$1  pas
K  /K:P$1  pas
L  /L:P$1  pas
M  /M:P$1  pas
N  /N:P$1  pas
P  /P:P$1  pas
R  /R:P$1  pas
S  /S:P$1  pas
T  /T:P$1  pas
U  /U:P$1  pas
V  /V:P$1  pas
W  /W:P$1  pas
X  /X:P$1  pas

## Footprint AS22-21 (pad centres in mm)
DEUTSCH Connector
drill 0.813 round: A 3.251,9.779; B 7.341,7.239; C 9.804,3.124; D 10.16,-1.651; E 8.331,-6.071; F 4.648,-9.195; G 0,-10.312; H -4.648,-9.195; J -8.331,-6.071; K -10.16,-1.651; L -9.804,3.124; M -7.341,7.239; N -3.251,9.779; P 0,6.223; R 4.064,3.708; S 5.436,-0.889; T 2.388,-4.928; U -2.388,-4.928; V -5.436,-0.889; W -4.064,3.708; X 0,0
hole 3.2 at -15.875,-15.875
hole 3.2 at 15.875,15.875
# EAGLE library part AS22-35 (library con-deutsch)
DEUTSCH Connector

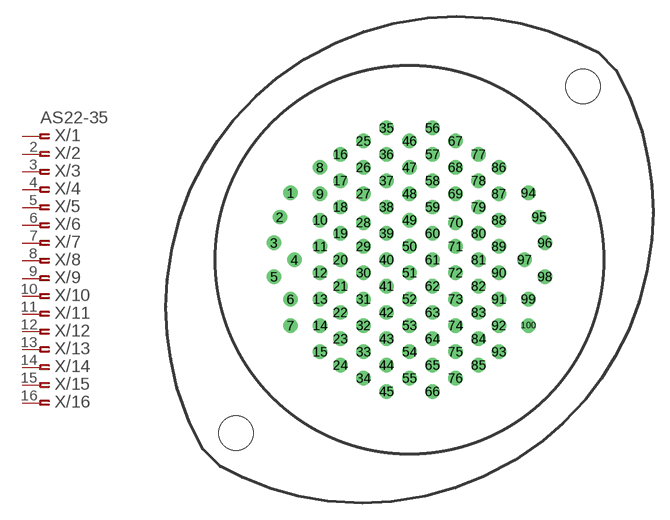
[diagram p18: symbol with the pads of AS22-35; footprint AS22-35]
Designator prefix X; gates /1=PINF_VAL /2=ASPINF /3=ASPINF /4=ASPINF /5=ASPINF /6=ASPINF /7=ASPINF /8=ASPINF /9=ASPINF /10=ASPINF /11=ASPINF /12=ASPINF /13=ASPINF /14=ASPINF /15=ASPINF /16=ASPINF /17=ASPINF /18=ASPINF /19=ASPINF /20=ASPINF /21=ASPINF /22=ASPINF /23=ASPINF /24=ASPINF /25=ASPINF /26=ASPINF /27=ASPINF /28=ASPINF /29=ASPINF /30=ASPINF /31=ASPINF /32=ASPINF /33=ASPINF /34=ASPINF /35=ASPINF /36=ASPINF /37=ASPINF /38=ASPINF /39=ASPINF /40=ASPINF /41=ASPINF /42=ASPINF /43=ASPINF /44=ASPINF /45=ASPINF /46=ASPINF /47=ASPINF /48=ASPINF /49=ASPINF /50=ASPINF /51=ASPINF /52=ASPINF /53=ASPINF /54=ASPINF /55=ASPINF /56=ASPINF /57=ASPINF /58=ASPINF /59=ASPINF /60=ASPINF /61=ASPINF /62=ASPINF /63=ASPINF /64=ASPINF /65=ASPINF /66=ASPINF /67=ASPINF /68=ASPINF /69=ASPINF /70=ASPINF /71=ASPINF /72=ASPINF /73=ASPINF /74=ASPINF /75=ASPINF /76=ASPINF /77=ASPINF /78=ASPINF /79=ASPINF /80=ASPINF /81=ASPINF /82=ASPINF /83=ASPINF /84=ASPINF /85=ASPINF /86=ASPINF /87=ASPINF /88=ASPINF /89=ASPINF /90=ASPINF /91=ASPINF /92=ASPINF /93=ASPINF /94=ASPINF /95=ASPINF /96=ASPINF /97=ASPINF /98=ASPINF /99=ASPINF /100=ASPINF

## AS22-35  [AS22-35]
1  /1:P$1  pas
2  /2:P$1  pas
3  /3:P$1  pas
4  /4:P$1  pas
5  /5:P$1  pas
6  /6:P$1  pas
7  /7:P$1  pas
8  /8:P$1  pas
9  /9:P$1  pas
10  /10:P$1  pas
11  /11:P$1  pas
12  /12:P$1  pas
13  /13:P$1  pas
14  /14:P$1  pas
15  /15:P$1  pas
16  /16:P$1  pas
17  /17:P$1  pas
18  /18:P$1  pas
19  /19:P$1  pas
20  /20:P$1  pas
21  /21:P$1  pas
22  /22:P$1  pas
23  /23:P$1  pas
24  /24:P$1  pas
25  /25:P$1  pas
26  /26:P$1  pas
27  /27:P$1  pas
28  /28:P$1  pas
29  /29:P$1  pas
30  /30:P$1  pas
31  /31:P$1  pas
32  /32:P$1  pas
33  /33:P$1  pas
34  /34:P$1  pas
35  /35:P$1  pas
36  /36:P$1  pas
37  /37:P$1  pas
38  /38:P$1  pas
39  /39:P$1  pas
40  /40:P$1  pas
41  /41:P$1  pas
42  /42:P$1  pas
43  /43:P$1  pas
44  /44:P$1  pas
45  /45:P$1  pas
46  /46:P$1  pas
47  /47:P$1  pas
48  /48:P$1  pas
49  /49:P$1  pas
50  /50:P$1  pas
51  /51:P$1  pas
52  /52:P$1  pas
53  /53:P$1  pas
54  /54:P$1  pas
55  /55:P$1  pas
56  /56:P$1  pas
57  /57:P$1  pas
58  /58:P$1  pas
59  /59:P$1  pas
60  /60:P$1  pas
61  /61:P$1  pas
62  /62:P$1  pas
63  /63:P$1  pas
64  /64:P$1  pas
65  /65:P$1  pas
66  /66:P$1  pas
67  /67:P$1  pas
68  /68:P$1  pas
69  /69:P$1  pas
70  /70:P$1  pas
71  /71:P$1  pas
72  /72:P$1  pas
73  /73:P$1  pas
74  /74:P$1  pas
75  /75:P$1  pas
76  /76:P$1  pas
77  /77:P$1  pas
78  /78:P$1  pas
79  /79:P$1  pas
80  /80:P$1  pas
81  /81:P$1  pas
82  /82:P$1  pas
83  /83:P$1  pas
84  /84:P$1  pas
85  /85:P$1  pas
86  /86:P$1  pas
87  /87:P$1  pas
88  /88:P$1  pas
89  /89:P$1  pas
90  /90:P$1  pas
91  /91:P$1  pas
92  /92:P$1  pas
93  /93:P$1  pas
94  /94:P$1  pas
95  /95:P$1  pas
96  /96:P$1  pas
97  /97:P$1  pas
98  /98:P$1  pas
99  /99:P$1  pas
100  /100:P$1  pas

## Footprint AS22-35 (pad centres in mm)
DEUTSCH Connector
drill 0.813 round: 1 -10.871,6.121; 2 -11.862,3.912; 3 -12.395,1.549; 4 -10.541,0; 5 -12.395,-1.549; 6 -10.871,-3.607; 7 -10.871,-6.02; 8 -8.179,8.458; 9 -8.179,6.045; 10 -8.179,3.632; 11 -8.179,1.219; 12 -8.179,-1.194; 13 -8.179,-3.607; 14 -8.179,-6.02; 15 -8.179,-8.433; 16 -6.325,9.652; 17 -6.325,7.239; 18 -6.325,4.826; 19 -6.325,2.413; 20 -6.325,0; 21 -6.325,-2.413; 22 -6.325,-4.826; 23 -6.325,-7.239; 24 -6.325,-9.652; 25 -4.216,10.871; 26 -4.216,8.458; 27 -4.216,6.045; 28 -4.216,3.404; 29 -4.216,1.219; 30 -4.216,-1.194; 31 -4.216,-3.607; 32 -4.216,-6.02; 33 -4.216,-8.433; 34 -4.216,-10.846; 35 -2.108,12.065; 36 -2.108,9.652; 37 -2.108,7.239; 38 -2.108,4.826; 39 -2.108,2.413; 40 -2.108,0; 41 -2.108,-2.413; 42 -2.108,-4.826; 43 -2.108,-7.239; 44 -2.108,-9.652; 45 -2.108,-12.065; 46 0,10.871; 47 0,8.458; 48 0,6.045; 49 0,3.632; 50 0,1.219; 51 0,-1.194; 52 0,-3.607; 53 0,-6.02; 54 0,-8.433; 55 0,-10.846; 56 2.108,12.065; 57 2.108,9.652; 58 2.108,7.239; 59 2.108,4.826; 60 2.108,2.413; 61 2.108,0; 62 2.108,-2.413; 63 2.108,-4.826; 64 2.108,-7.239; 65 2.108,-9.652; 66 2.108,-12.065; 67 4.216,10.871; 68 4.216,8.458; 69 4.216,6.045; 70 4.216,3.404; 71 4.216,1.219; 72 4.216,-1.194; 73 4.216,-3.607; 74 4.216,-6.02; 75 4.216,-8.433; 76 4.216,-10.846; 77 6.325,9.652; 78 6.325,7.239; 79 6.325,4.826; 80 6.325,2.413; 81 6.325,0; 82 6.325,-2.413; 83 6.325,-4.826; 84 6.325,-7.239; 85 6.325,-9.652; 86 8.179,8.458; 87 8.179,6.045; 88 8.179,3.632; 89 8.179,1.219; 90 8.179,-1.194; 91 8.179,-3.607; 92 8.179,-6.02; 93 8.179,-8.433; 94 10.871,6.121; 95 11.862,3.912; 96 12.395,1.549; 97 10.541,0; 98 12.395,-1.549; 99 10.871,-3.607; 100 10.871,-6.02
hole 3.2 at -15.875,-15.875
hole 3.2 at 15.875,15.875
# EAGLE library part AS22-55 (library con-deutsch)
DEUTSCH Connector

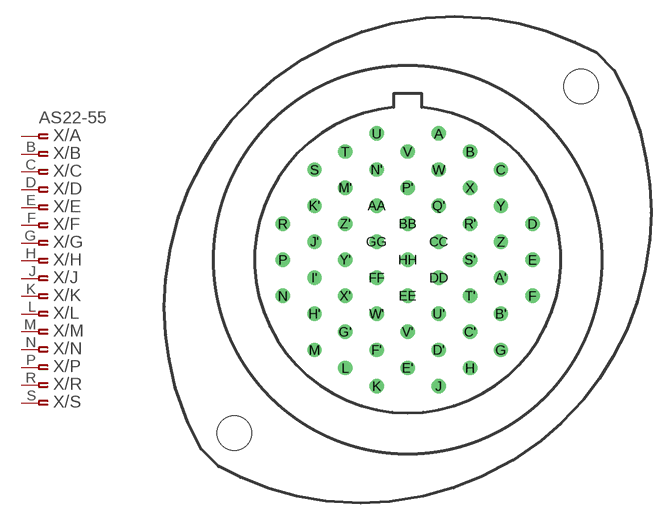
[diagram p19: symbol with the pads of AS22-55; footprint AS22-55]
Designator prefix X; gates /A=PINF_VAL /B=ASPINF /C=ASPINF /D=ASPINF /E=ASPINF /F=ASPINF /G=ASPINF /H=ASPINF /J=ASPINF /K=ASPINF /L=ASPINF /M=ASPINF /N=ASPINF /P=ASPINF /R=ASPINF /S=ASPINF /T=ASPINF /U=ASPINF /V=ASPINF /W=ASPINF /X=ASPINF /Y=ASPINF /Z=ASPINF /A'=PINF_VAL /B'=ASPINF /C'=ASPINF /D'=ASPINF /E'=ASPINF /F'=ASPINF /G'=ASPINF /H'=ASPINF /J'=ASPINF /K'=ASPINF /I'=ASPINF /M'=ASPINF /N'=ASPINF /P'=ASPINF /R'=ASPINF /S'=ASPINF /T'=ASPINF /U'=ASPINF /V'=ASPINF /W'=ASPINF /X'=ASPINF /Y'=ASPINF /Z'=ASPINF /Q'=ASPINF /AA=PINF_VAL /BB=ASPINF /CC=ASPINF /DD=ASPINF /EE=ASPINF /FF=ASPINF /GG=ASPINF /HH=ASPINF

## AS22-55  [AS22-55]
A  /A:P$1  pas
A'  /A':P$1  pas
AA  /AA:P$1  pas
B  /B:P$1  pas
B'  /B':P$1  pas
BB  /BB:P$1  pas
C  /C:P$1  pas
C'  /C':P$1  pas
CC  /CC:P$1  pas
D  /D:P$1  pas
D'  /D':P$1  pas
DD  /DD:P$1  pas
E  /E:P$1  pas
E'  /E':P$1  pas
EE  /EE:P$1  pas
F  /F:P$1  pas
F'  /F':P$1  pas
FF  /FF:P$1  pas
G  /G:P$1  pas
G'  /G':P$1  pas
GG  /GG:P$1  pas
H  /H:P$1  pas
H'  /H':P$1  pas
HH  /HH:P$1  pas
I'  /I':P$1  pas
J  /J:P$1  pas
J'  /J':P$1  pas
K  /K:P$1  pas
K'  /K':P$1  pas
L  /L:P$1  pas
M  /M:P$1  pas
M'  /M':P$1  pas
N  /N:P$1  pas
N'  /N':P$1  pas
P  /P:P$1  pas
P'  /P':P$1  pas
Q'  /Q':P$1  pas
R  /R:P$1  pas
R'  /R':P$1  pas
S  /S:P$1  pas
S'  /S':P$1  pas
T  /T:P$1  pas
T'  /T':P$1  pas
U  /U:P$1  pas
U'  /U':P$1  pas
V  /V:P$1  pas
V'  /V':P$1  pas
W  /W:P$1  pas
W'  /W':P$1  pas
X  /X:P$1  pas
X'  /X':P$1  pas
Y  /Y:P$1  pas
Y'  /Y':P$1  pas
Z  /Z:P$1  pas
Z'  /Z':P$1  pas

## Footprint AS22-55 (pad centres in mm)
DEUTSCH Connector
drill 0.813 round: A 2.845,11.557; A' 8.534,-1.651; AA -2.845,4.953; B 5.715,9.906; B' 8.534,-4.953; BB 0,3.302; C 8.534,8.255; C' 5.715,-6.604; CC 2.845,1.651; D 11.43,3.302; D' 2.845,-8.255; DD 2.845,-1.651; E 11.43,0; E' 0,-9.906; EE 0,-3.302; F 11.43,-3.302; F' -2.845,-8.255; FF -2.845,-1.651; G 8.534,-8.255; G' -5.715,-6.604; GG -2.845,1.651; H 5.715,-9.906; H' -8.534,-4.953; HH 0,0; I' -8.534,-1.651; J 2.845,-11.557; J' -8.534,1.651; K -2.845,-11.557; K' -8.534,4.953; L -5.715,-9.906; M -8.534,-8.255; M' -5.715,6.604; N -11.43,-3.302; N' -2.845,8.255; P -11.43,0; P' 0,6.604; Q' 2.845,4.953; R -11.43,3.302; R' 5.715,3.302; S -8.534,8.255; S' 5.715,0; T -5.715,9.906; T' 5.715,-3.302; U -2.845,11.557; U' 2.845,-4.953; V 0,9.906; V' 0,-6.604; W 2.845,8.255; W' -2.845,-4.953; X 5.715,6.604; X' -5.715,-3.302; Y 8.534,4.953; Y' -5.715,0; Z 8.534,1.651; Z' -5.715,3.302
hole 3.2 at -15.875,-15.875
hole 3.2 at 15.875,15.875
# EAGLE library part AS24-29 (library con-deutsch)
DEUTSCH Connector

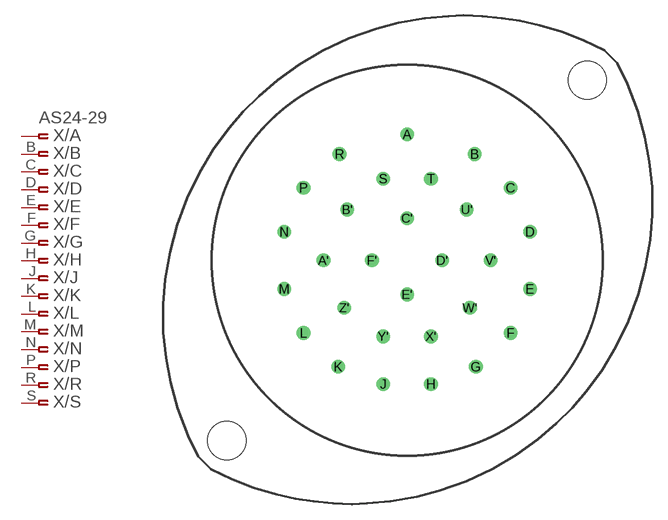
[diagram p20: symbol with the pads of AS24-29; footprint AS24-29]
Designator prefix X; gates /A=PINF_VAL /B=ASPINF /C=ASPINF /D=ASPINF /E=ASPINF /F=ASPINF /G=ASPINF /H=ASPINF /J=ASPINF /K=ASPINF /L=ASPINF /M=ASPINF /N=ASPINF /P=ASPINF /R=ASPINF /S=ASPINF /T=ASPINF /A'=PINF_VAL /B'=ASPINF /C'=ASPINF /D'=ASPINF /E'=ASPINF /F'=ASPINF /U'=ASPINF /V'=ASPINF /W'=ASPINF /X'=ASPINF /Y'=ASPINF /Z'=ASPINF

## AS24-29  [AS24-29]
A  /A:P$1  pas
A'  /A':P$1  pas
B  /B:P$1  pas
B'  /B':P$1  pas
C  /C:P$1  pas
C'  /C':P$1  pas
D  /D:P$1  pas
D'  /D':P$1  pas
E  /E:P$1  pas
E'  /E':P$1  pas
F  /F:P$1  pas
F'  /F':P$1  pas
G  /G:P$1  pas
H  /H:P$1  pas
J  /J:P$1  pas
K  /K:P$1  pas
L  /L:P$1  pas
M  /M:P$1  pas
N  /N:P$1  pas
P  /P:P$1  pas
R  /R:P$1  pas
S  /S:P$1  pas
T  /T:P$1  pas
U'  /U':P$1  pas
V'  /V':P$1  pas
W'  /W':P$1  pas
X'  /X':P$1  pas
Y'  /Y':P$1  pas
Z'  /Z':P$1  pas

## Footprint AS24-29 (pad centres in mm)
DEUTSCH Connector
drill 0.813 round: A 0,12.217; A' -8.103,0; B 6.553,10.312; B' -5.791,4.928; C 10.033,7.036; C' 0,4.089; D 11.913,2.769; D' 3.404,0; E 11.913,-2.769; E' 0,-3.302; F 10.033,-7.036; F' -3.404,0; G 6.68,-10.312; H 2.311,-11.989; J -2.311,-11.989; K -6.68,-10.312; L -10.033,-7.036; M -11.913,-2.769; N -11.913,2.769; P -10.033,7.036; R -6.553,10.312; S -2.311,7.925; T 2.311,7.925; U' 5.791,4.928; V' 8.103,0; W' 6.096,-4.597; X' 2.311,-7.366; Y' -2.311,-7.366; Z' -6.096,-4.597
hole 3.7 at -17.462,-17.462
hole 3.7 at 17.462,17.462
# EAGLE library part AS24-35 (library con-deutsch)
DEUTSCH Connector

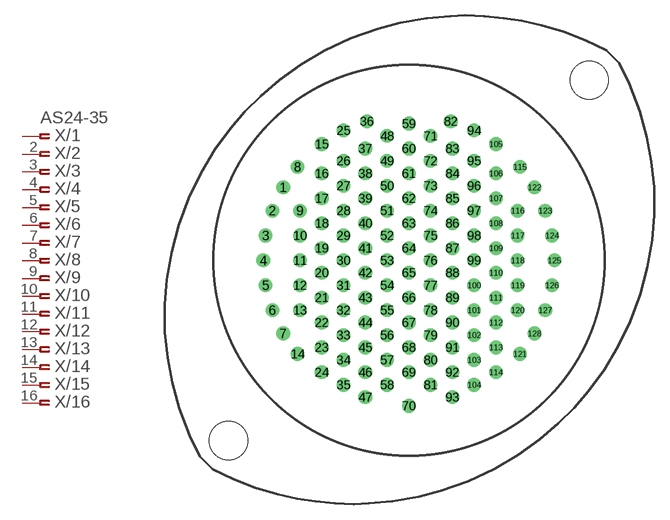
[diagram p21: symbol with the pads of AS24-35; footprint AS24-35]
Designator prefix X; gates /1=PINF_VAL /2=ASPINF /3=ASPINF /4=ASPINF /5=ASPINF /6=ASPINF /7=ASPINF /8=ASPINF /9=ASPINF /10=ASPINF /11=ASPINF /12=ASPINF /13=ASPINF /14=ASPINF /15=ASPINF /16=ASPINF /17=ASPINF /18=ASPINF /19=ASPINF /20=ASPINF /21=ASPINF /22=ASPINF /23=ASPINF /24=ASPINF /25=ASPINF /26=ASPINF /27=ASPINF /28=ASPINF /29=ASPINF /30=ASPINF /31=ASPINF /32=ASPINF /33=ASPINF /34=ASPINF /35=ASPINF /36=ASPINF /37=ASPINF /38=ASPINF /39=ASPINF /40=ASPINF /41=ASPINF /42=ASPINF /43=ASPINF /44=ASPINF /45=ASPINF /46=ASPINF /47=ASPINF /48=ASPINF /49=ASPINF /50=ASPINF /51=ASPINF /52=ASPINF /53=ASPINF /54=ASPINF /55=ASPINF /56=ASPINF /57=ASPINF /58=ASPINF /59=ASPINF /60=ASPINF /61=ASPINF /62=ASPINF /63=ASPINF /64=ASPINF /65=ASPINF /66=ASPINF /67=ASPINF /68=ASPINF /69=ASPINF /70=ASPINF /71=ASPINF /72=ASPINF /73=ASPINF /74=ASPINF /75=ASPINF /76=ASPINF /77=ASPINF /78=ASPINF /79=ASPINF /80=ASPINF /81=ASPINF /82=ASPINF /83=ASPINF /84=ASPINF /85=ASPINF /86=ASPINF /87=ASPINF /88=ASPINF /89=ASPINF /90=ASPINF /91=ASPINF /92=ASPINF /93=ASPINF /94=ASPINF /95=ASPINF /96=ASPINF /97=ASPINF /98=ASPINF /99=ASPINF /100=ASPINF /101=ASPINF /102=ASPINF /103=ASPINF /104=ASPINF /105=ASPINF /106=ASPINF /107=ASPINF /108=ASPINF /109=ASPINF /110=ASPINF /111=ASPINF /112=ASPINF /113=ASPINF /114=ASPINF /115=ASPINF /116=ASPINF /117=ASPINF /118=ASPINF /119=ASPINF /120=ASPINF /121=ASPINF /122=ASPINF /123=ASPINF /124=ASPINF /125=ASPINF /126=ASPINF /127=ASPINF /128=ASPINF

## AS24-35  [AS24-35]
1  /1:P$1  pas
2  /2:P$1  pas
3  /3:P$1  pas
4  /4:P$1  pas
5  /5:P$1  pas
6  /6:P$1  pas
7  /7:P$1  pas
8  /8:P$1  pas
9  /9:P$1  pas
10  /10:P$1  pas
11  /11:P$1  pas
12  /12:P$1  pas
13  /13:P$1  pas
14  /14:P$1  pas
15  /15:P$1  pas
16  /16:P$1  pas
17  /17:P$1  pas
18  /18:P$1  pas
19  /19:P$1  pas
20  /20:P$1  pas
21  /21:P$1  pas
22  /22:P$1  pas
23  /23:P$1  pas
24  /24:P$1  pas
25  /25:P$1  pas
26  /26:P$1  pas
27  /27:P$1  pas
28  /28:P$1  pas
29  /29:P$1  pas
30  /30:P$1  pas
31  /31:P$1  pas
32  /32:P$1  pas
33  /33:P$1  pas
34  /34:P$1  pas
35  /35:P$1  pas
36  /36:P$1  pas
37  /37:P$1  pas
38  /38:P$1  pas
39  /39:P$1  pas
40  /40:P$1  pas
41  /41:P$1  pas
42  /42:P$1  pas
43  /43:P$1  pas
44  /44:P$1  pas
45  /45:P$1  pas
46  /46:P$1  pas
47  /47:P$1  pas
48  /48:P$1  pas
49  /49:P$1  pas
50  /50:P$1  pas
51  /51:P$1  pas
52  /52:P$1  pas
53  /53:P$1  pas
54  /54:P$1  pas
55  /55:P$1  pas
56  /56:P$1  pas
57  /57:P$1  pas
58  /58:P$1  pas
59  /59:P$1  pas
60  /60:P$1  pas
61  /61:P$1  pas
62  /62:P$1  pas
63  /63:P$1  pas
64  /64:P$1  pas
65  /65:P$1  pas
66  /66:P$1  pas
67  /67:P$1  pas
68  /68:P$1  pas
69  /69:P$1  pas
70  /70:P$1  pas
71  /71:P$1  pas
72  /72:P$1  pas
73  /73:P$1  pas
74  /74:P$1  pas
75  /75:P$1  pas
76  /76:P$1  pas
77  /77:P$1  pas
78  /78:P$1  pas
79  /79:P$1  pas
80  /80:P$1  pas
81  /81:P$1  pas
82  /82:P$1  pas
83  /83:P$1  pas
84  /84:P$1  pas
85  /85:P$1  pas
86  /86:P$1  pas
87  /87:P$1  pas
88  /88:P$1  pas
89  /89:P$1  pas
90  /90:P$1  pas
91  /91:P$1  pas
92  /92:P$1  pas
93  /93:P$1  pas
94  /94:P$1  pas
95  /95:P$1  pas
96  /96:P$1  pas
97  /97:P$1  pas
98  /98:P$1  pas
99  /99:P$1  pas
100  /100:P$1  pas
101  /101:P$1  pas
102  /102:P$1  pas
103  /103:P$1  pas
104  /104:P$1  pas
105  /105:P$1  pas
106  /106:P$1  pas
107  /107:P$1  pas
108  /108:P$1  pas
109  /109:P$1  pas
110  /110:P$1  pas
111  /111:P$1  pas
112  /112:P$1  pas
113  /113:P$1  pas
114  /114:P$1  pas
115  /115:P$1  pas
116  /116:P$1  pas
117  /117:P$1  pas
118  /118:P$1  pas
119  /119:P$1  pas
120  /120:P$1  pas
121  /121:P$1  pas
122  /122:P$1  pas
123  /123:P$1  pas
124  /124:P$1  pas
125  /125:P$1  pas
126  /126:P$1  pas
127  /127:P$1  pas
128  /128:P$1  pas

## Footprint AS24-35 (pad centres in mm)
DEUTSCH Connector
drill 0.813 round: 1 -12.167,7.087; 2 -13.208,4.826; 3 -13.868,2.413; 4 -14.097,0; 5 -13.868,-2.413; 6 -13.208,-4.826; 7 -12.167,-7.087; 8 -10.77,9.068; 9 -10.541,4.826; 10 -10.541,2.413; 11 -10.541,0; 12 -10.541,-2.413; 13 -10.541,-4.826; 14 -10.77,-9.068; 15 -8.433,11.278; 16 -8.433,8.433; 17 -8.433,6.02; 18 -8.433,3.607; 19 -8.433,1.194; 20 -8.433,-1.194; 21 -8.433,-3.607; 22 -8.433,-6.02; 23 -8.433,-8.433; 24 -8.433,-10.846; 25 -6.325,12.598; 26 -6.325,9.652; 27 -6.325,7.239; 28 -6.325,4.826; 29 -6.325,2.413; 30 -6.325,0; 31 -6.325,-2.413; 32 -6.325,-4.826; 33 -6.325,-7.239; 34 -6.325,-9.652; 35 -6.325,-12.065; 36 -4.064,13.487; 37 -4.216,10.846; 38 -4.216,8.433; 39 -4.216,6.02; 40 -4.216,3.607; 41 -4.216,1.194; 42 -4.216,-1.194; 43 -4.216,-3.607; 44 -4.216,-6.02; 45 -4.216,-8.433; 46 -4.216,-10.846; 47 -4.216,-13.259; 48 -2.108,12.065; 49 -2.108,9.652; 50 -2.108,7.239; 51 -2.108,4.826; 52 -2.108,2.413; 53 -2.108,0; 54 -2.108,-2.413; 55 -2.108,-4.826; 56 -2.108,-7.239; 57 -2.108,-9.652; 58 -2.108,-12.065; 59 0,13.259; 60 0,10.846; 61 0,8.433; 62 0,6.02; 63 0,3.607; 64 0,1.194; 65 0,-1.194; 66 0,-3.607; 67 0,-6.02; 68 0,-8.433; 69 0,-10.846; 70 0,-14.097; 71 2.108,12.065; 72 2.108,9.652; 73 2.108,7.239; 74 2.108,4.826; 75 2.108,2.413; 76 2.108,0; 77 2.108,-2.413; 78 2.108,-4.826; 79 2.108,-7.239; 80 2.108,-9.652; 81 2.108,-12.065; 82 4.064,13.487; 83 4.216,10.846; 84 4.216,8.433; 85 4.216,6.02; 86 4.216,3.607; 87 4.216,1.194; 88 4.216,-1.194; 89 4.216,-3.607; 90 4.216,-6.02; 91 4.216,-8.433; 92 4.216,-10.846; 93 4.216,-13.259; 94 6.325,12.598; 95 6.325,9.652; 96 6.325,7.239; 97 6.325,4.826; 98 6.325,2.413; 99 6.325,0; 100 6.325,-2.413; 101 6.325,-4.826; 102 6.325,-7.239; 103 6.325,-9.652; 104 6.325,-12.065; 105 8.433,11.278; 106 8.433,8.433; 107 8.433,6.02; 108 8.433,3.607; 109 8.433,1.194; 110 8.433,-1.194; 111 8.433,-3.607; 112 8.433,-6.02; 113 8.433,-8.433; 114 8.433,-10.846; 115 10.77,9.068; 116 10.541,4.826; 117 10.541,2.413; 118 10.541,0; 119 10.541,-2.413; 120 10.541,-4.826; 121 10.77,-9.068; 122 12.167,7.087; 123 13.208,4.826; 124 13.868,2.413; 125 14.097,0; 126 13.868,-2.413; 127 13.208,-4.826; 128 12.167,-7.087
hole 3.7 at -17.462,-17.462
hole 3.7 at 17.462,17.462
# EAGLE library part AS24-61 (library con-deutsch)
DEUTSCH Connector

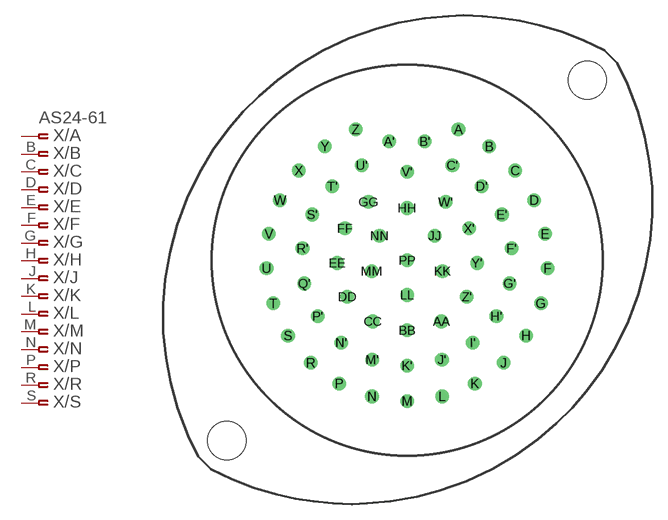
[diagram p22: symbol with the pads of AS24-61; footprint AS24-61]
Designator prefix X; gates /A=PINF_VAL /B=ASPINF /C=ASPINF /D=ASPINF /E=ASPINF /F=ASPINF /G=ASPINF /H=ASPINF /J=ASPINF /K=ASPINF /L=ASPINF /M=ASPINF /N=ASPINF /P=ASPINF /R=ASPINF /S=ASPINF /T=ASPINF /U=ASPINF /V=ASPINF /W=ASPINF /X=ASPINF /Y=ASPINF /Z=ASPINF /A'=PINF_VAL /B'=ASPINF /C'=ASPINF /D'=ASPINF /E'=ASPINF /F'=ASPINF /G'=ASPINF /H'=ASPINF /J'=ASPINF /K'=ASPINF /M'=ASPINF /N'=ASPINF /P'=ASPINF /R'=ASPINF /S'=ASPINF /T'=ASPINF /U'=ASPINF /V'=ASPINF /W'=ASPINF /X'=ASPINF /Y'=ASPINF /Z'=ASPINF /AA=PINF_VAL /BB=ASPINF /CC=ASPINF /DD=ASPINF /EE=ASPINF /FF=ASPINF /GG=ASPINF /HH=ASPINF /JJ=ASPINF /KK=ASPINF /LL=ASPINF /MM=ASPINF /NN=ASPINF /PP=ASPINF /I'=ASPINF /Q'=ASPINF

## AS24-61  [AS24-61]
A  /A:P$1  pas
A'  /A':P$1  pas
AA  /AA:P$1  pas
B  /B:P$1  pas
B'  /B':P$1  pas
BB  /BB:P$1  pas
C  /C:P$1  pas
C'  /C':P$1  pas
CC  /CC:P$1  pas
D  /D:P$1  pas
D'  /D':P$1  pas
DD  /DD:P$1  pas
E  /E:P$1  pas
E'  /E':P$1  pas
EE  /EE:P$1  pas
F  /F:P$1  pas
F'  /F':P$1  pas
FF  /FF:P$1  pas
G  /G:P$1  pas
G'  /G':P$1  pas
GG  /GG:P$1  pas
H  /H:P$1  pas
H'  /H':P$1  pas
HH  /HH:P$1  pas
I'  /I':P$1  pas
J  /J:P$1  pas
J'  /J':P$1  pas
JJ  /JJ:P$1  pas
K  /K:P$1  pas
K'  /K':P$1  pas
KK  /KK:P$1  pas
L  /L:P$1  pas
LL  /LL:P$1  pas
M  /M:P$1  pas
M'  /M':P$1  pas
MM  /MM:P$1  pas
N  /N:P$1  pas
N'  /N':P$1  pas
NN  /NN:P$1  pas
P  /P:P$1  pas
P'  /P':P$1  pas
PP  /PP:P$1  pas
Q'  /Q':P$1  pas
R  /R:P$1  pas
R'  /R':P$1  pas
S  /S:P$1  pas
S'  /S':P$1  pas
T  /T:P$1  pas
T'  /T':P$1  pas
U  /U:P$1  pas
U'  /U':P$1  pas
V  /V:P$1  pas
V'  /V':P$1  pas
W  /W:P$1  pas
W'  /W':P$1  pas
X  /X:P$1  pas
X'  /X':P$1  pas
Y  /Y:P$1  pas
Y'  /Y':P$1  pas
Z  /Z:P$1  pas
Z'  /Z':P$1  pas

## Footprint AS24-61 (pad centres in mm)
DEUTSCH Connector
drill 0.813 round: A 4.978,12.7; A' -1.727,11.532; AA 3.327,-5.918; B 7.976,11.049; B' 1.727,11.532; BB 0,-6.782; C 10.49,8.712; C' 4.394,9.22; CC -3.327,-5.918; D 12.319,5.842; D' 7.239,7.188; DD -5.791,-3.531; E 13.386,2.565; E' 9.195,4.445; EE -6.782,-0.254; F 13.614,-0.762; F' 10.135,1.168; FF -6.02,3.099; G 12.979,-4.166; G' 9.957,-2.235; GG -3.734,5.664; H 11.532,-7.29; H' 8.661,-5.41; HH 0,5.08; I' 6.375,-7.976; J 9.347,-9.931; J' 3.378,-9.627; JJ 2.667,2.388; K 6.579,-11.938; K' 0,-10.211; KK 3.429,-1.041; L 3.404,-13.183; LL 0,-3.353; M 0,-13.64; M' -3.378,-9.627; MM -3.429,-1.041; N -3.404,-13.183; N' -6.375,-7.976; NN -2.667,2.388; P -6.579,-11.938; P' -8.661,-5.41; PP 0,0; Q' -9.957,-2.235; R -9.347,-9.931; R' -10.135,1.168; S -11.532,-7.29; S' -9.195,4.445; T -12.979,-4.166; T' -7.239,7.188; U -13.614,-0.762; U' -4.394,9.22; V -13.386,2.565; V' 0,8.585; W -12.319,5.842; W' 3.734,5.664; X -10.49,8.712; X' 6.02,3.099; Y -7.976,11.049; Y' 6.782,-0.254; Z -4.978,12.7; Z' 5.791,-3.531
hole 3.7 at -17.462,-17.462
hole 3.7 at 17.462,17.462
